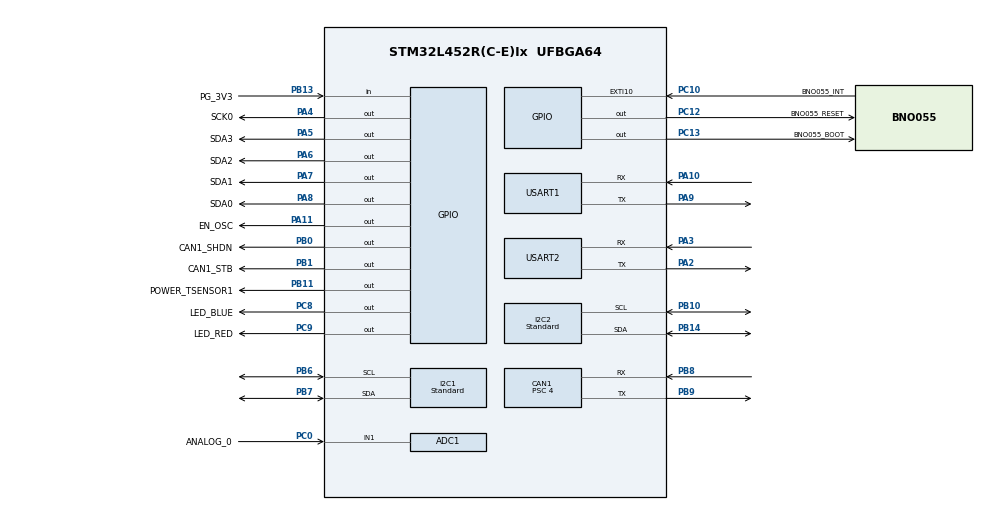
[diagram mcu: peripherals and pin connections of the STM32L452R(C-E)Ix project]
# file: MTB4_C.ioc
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ADC1.Channel-1\#ChannelRegularConversion=ADC_CHANNEL_1
ADC1.NbrOfConversionFlag=1
ADC1.OffsetNumber-1\#ChannelRegularConversion=ADC_OFFSET_NONE
ADC1.Rank-1\#ChannelRegularConversion=1
ADC1.SamplingTime-1\#ChannelRegularConversion=ADC_SAMPLETIME_2CYCLES_5
ADC1.master=1
CAN1.ABOM=ENABLE
CAN1.AWUM=ENABLE
CAN1.BS1=CAN_BS1_4TQ
CAN1.BS2=CAN_BS2_3TQ
CAN1.CalculateBaudRate=1000000
CAN1.CalculateTimeBit=1000
CAN1.CalculateTimeQuantum=125.0
CAN1.NART=ENABLE
CAN1.Prescaler=4
Dma.I2C1_RX.3.Direction=DMA_PERIPH_TO_MEMORY
Dma.I2C1_RX.3.Instance=DMA1_Channel7
Dma.I2C1_RX.3.MemDataAlignment=DMA_MDATAALIGN_BYTE
Dma.I2C1_RX.3.MemInc=DMA_MINC_ENABLE
Dma.I2C1_RX.3.Mode=DMA_NORMAL
Dma.I2C1_RX.3.PeriphDataAlignment=DMA_PDATAALIGN_BYTE
Dma.I2C1_RX.3.PeriphInc=DMA_PINC_DISABLE
Dma.I2C1_RX.3.Priority=DMA_PRIORITY_LOW
Dma.I2C1_TX.2.Direction=DMA_MEMORY_TO_PERIPH
Dma.I2C1_TX.2.Instance=DMA1_Channel6
Dma.I2C1_TX.2.MemDataAlignment=DMA_MDATAALIGN_BYTE
Dma.I2C1_TX.2.MemInc=DMA_MINC_ENABLE
Dma.I2C1_TX.2.Mode=DMA_NORMAL
Dma.I2C1_TX.2.PeriphDataAlignment=DMA_PDATAALIGN_BYTE
Dma.I2C1_TX.2.PeriphInc=DMA_PINC_DISABLE
Dma.I2C1_TX.2.Priority=DMA_PRIORITY_LOW
Dma.I2C2_RX.1.Direction=DMA_PERIPH_TO_MEMORY
Dma.I2C2_RX.1.Instance=DMA1_Channel5
Dma.I2C2_RX.1.MemDataAlignment=DMA_MDATAALIGN_BYTE
Dma.I2C2_RX.1.MemInc=DMA_MINC_ENABLE
Dma.I2C2_RX.1.Mode=DMA_NORMAL
Dma.I2C2_RX.1.PeriphDataAlignment=DMA_PDATAALIGN_BYTE
Dma.I2C2_RX.1.PeriphInc=DMA_PINC_DISABLE
Dma.I2C2_RX.1.Priority=DMA_PRIORITY_LOW
Dma.I2C2_TX.0.Direction=DMA_MEMORY_TO_PERIPH
Dma.I2C2_TX.0.Instance=DMA1_Channel4
Dma.I2C2_TX.0.MemDataAlignment=DMA_MDATAALIGN_BYTE
Dma.I2C2_TX.0.MemInc=DMA_MINC_ENABLE
Dma.I2C2_TX.0.Mode=DMA_NORMAL
Dma.I2C2_TX.0.PeriphDataAlignment=DMA_PDATAALIGN_BYTE
Dma.I2C2_TX.0.PeriphInc=DMA_PINC_DISABLE
Dma.I2C2_TX.0.Priority=DMA_PRIORITY_LOW
Dma.Request0=I2C2_TX
Dma.Request1=I2C2_RX
Dma.Request2=I2C1_TX
Dma.Request3=I2C1_RX
Dma.Request4=USART1_TX
Dma.Request5=USART1_RX
Dma.USART1_RX.5.Direction=DMA_PERIPH_TO_MEMORY
Dma.USART1_RX.5.Instance=DMA2_Channel7
Dma.USART1_RX.5.MemDataAlignment=DMA_MDATAALIGN_BYTE
Dma.USART1_RX.5.MemInc=DMA_MINC_ENABLE
Dma.USART1_RX.5.Mode=DMA_NORMAL
Dma.USART1_RX.5.PeriphDataAlignment=DMA_PDATAALIGN_BYTE
Dma.USART1_RX.5.PeriphInc=DMA_PINC_DISABLE
Dma.USART1_RX.5.Priority=DMA_PRIORITY_LOW
Dma.USART1_TX.4.Direction=DMA_MEMORY_TO_PERIPH
Dma.USART1_TX.4.Instance=DMA2_Channel6
Dma.USART1_TX.4.MemDataAlignment=DMA_MDATAALIGN_BYTE
Dma.USART1_TX.4.MemInc=DMA_MINC_ENABLE
Dma.USART1_TX.4.Mode=DMA_NORMAL
Dma.USART1_TX.4.PeriphDataAlignment=DMA_PDATAALIGN_BYTE
Dma.USART1_TX.4.PeriphInc=DMA_PINC_DISABLE
Dma.USART1_TX.4.Priority=DMA_PRIORITY_LOW
I2C1.CustomTiming=Disabled
I2C1.I2C_Speed_Mode=I2C_Standard
I2C1.NoStretchMode=I2C_NOSTRETCH_DISABLE
I2C1.Timing=0x00707CBB
I2C2.I2C_Speed_Mode=I2C_Standard
I2C2.NoStretchMode=I2C_NOSTRETCH_DISABLE
I2C2.Timing=0x00707CBB
Mcu.Family=STM32L4
Mcu.Name=STM32L452R(C-E)Ix
Mcu.Package=UFBGA64
NVIC.CAN1_RX0_IRQn=true\:0\:0\:false\:false\:true\:true\:true\:true
NVIC.CAN1_TX_IRQn=true\:0\:0\:false\:false\:true\:true\:true\:true
NVIC.DMA1_Channel4_IRQn=true\:0\:0\:false\:false\:true\:false\:true\:true
NVIC.DMA1_Channel5_IRQn=true\:0\:0\:false\:false\:true\:false\:true\:true
NVIC.DMA1_Channel6_IRQn=true\:0\:0\:false\:false\:true\:false\:true\:true
NVIC.DMA1_Channel7_IRQn=true\:0\:0\:false\:false\:true\:false\:true\:true
NVIC.DMA2_Channel6_IRQn=true\:0\:0\:false\:false\:true\:false\:true\:true
NVIC.DMA2_Channel7_IRQn=true\:0\:0\:false\:false\:true\:false\:true\:true
NVIC.I2C1_ER_IRQn=true\:0\:0\:false\:false\:true\:true\:true\:true
NVIC.I2C1_EV_IRQn=true\:0\:0\:false\:false\:true\:true\:true\:true
NVIC.I2C2_ER_IRQn=true\:0\:0\:false\:false\:true\:true\:true\:true
NVIC.I2C2_EV_IRQn=true\:0\:0\:false\:false\:true\:true\:true\:true
NVIC.PriorityGroup=NVIC_PRIORITYGROUP_4
NVIC.TIM6_DAC_IRQn=true\:0\:0\:false\:false\:true\:true\:true\:true
PA10.Mode=Asynchronous
PA10.Signal=USART1_RX
PA11.GPIO_Label=EN_OSC
PA11.Signal=GPIO_Output
PA13\ (JTMS/SWDIO).Mode=Serial_Wire
PA13\ (JTMS/SWDIO).Signal=SYS_JTMS-SWDIO
PA14\ (JTCK/SWCLK).Mode=Serial_Wire
PA14\ (JTCK/SWCLK).Signal=SYS_JTCK-SWCLK
PA2.Mode=Asynchronous
PA2.Signal=USART2_TX
PA3.Mode=Asynchronous
PA3.Signal=USART2_RX
PA4.GPIO_Label=SCK0
PA4.Signal=GPIO_Output
PA5.GPIO_Label=SDA3
PA5.Signal=GPIO_Output
PA6.GPIO_Label=SDA2
PA6.Signal=GPIO_Output
PA7.GPIO_Label=SDA1
PA7.Signal=GPIO_Output
PA8.GPIO_Label=SDA0
PA8.Signal=GPIO_Output
PA9.Mode=Asynchronous
PA9.Signal=USART1_TX
PB0.GPIO_Label=CAN1_SHDN
PB0.Signal=GPIO_Output
PB1.GPIO_Label=CAN1_STB
PB1.Signal=GPIO_Output
PB10.GPIO_Pu=GPIO_PULLUP
PB10.Mode=I2C
PB10.Signal=I2C2_SCL
PB11.GPIO_Label=POWER_TSENSOR1
PB11.Signal=GPIO_Output
PB13.GPIO_Label=PG_3V3
PB13.Signal=GPIO_Input
PB14.GPIO_Pu=GPIO_PULLUP
PB14.Mode=I2C
PB14.Signal=I2C2_SDA
PB6.GPIO_Pu=GPIO_PULLUP
PB6.Mode=I2C
PB6.Signal=I2C1_SCL
PB7.GPIO_Pu=GPIO_PULLUP
PB7.Mode=I2C
PB7.Signal=I2C1_SDA
PB8.Mode=CAN_Activate
PB8.Signal=CAN1_RX
PB9.Mode=CAN_Activate
PB9.Signal=CAN1_TX
PC0.GPIO_Label=ANALOG_0
PC0.Signal=ADCx_IN1
PC10.GPIO_Label=BNO055_INT
PC10.Signal=GPXTI10
PC12.GPIO_Label=BNO055_RESET
PC12.Signal=GPIO_Output
PC13.GPIO_Label=BNO055_BOOT
PC13.Signal=GPIO_Output
PC8.GPIO_Label=LED_BLUE
PC8.Signal=GPIO_Output
PC9.GPIO_Label=LED_RED
PC9.Signal=GPIO_Output
PH0-OSC_IN\ (PH0).Mode=HSE-External-Clock-Source
PH0-OSC_IN\ (PH0).Signal=RCC_OSC_IN
ProjectManager.HeapSize=0x200
ProjectManager.StackSize=0x400
ProjectManager.TargetToolchain=MDK-ARM V5.32
RCC.ADCFreq_Value=32000000
RCC.AHBFreq_Value=32000000
RCC.APB1Freq_Value=32000000
RCC.APB1TimFreq_Value=32000000
RCC.APB2Freq_Value=32000000
RCC.APB2TimFreq_Value=32000000
RCC.CortexFreq_Value=32000000
RCC.HCLKFreq_Value=32000000
RCC.HSE_VALUE=10000000
RCC.HSI48_VALUE=48000000
RCC.HSI_VALUE=16000000
RCC.LSE_VALUE=32768
RCC.MSI_VALUE=4000000
RCC.PLLM=4
RCC.PLLN=16
RCC.PLLSAI1N=16
RCC.PLLSAI1Q=RCC_PLLQ_DIV4
RCC.PLLSourceVirtual=RCC_PLLSOURCE_HSI
RCC.SYSCLKFreq_VALUE=32000000
RCC.SYSCLKSource=RCC_SYSCLKSOURCE_PLLCLK
RCC.USBFreq_Value=16000000
RCC.VCOOutputFreq_Value=64000000
SH.ADCx_IN1.0=ADC1_IN1,IN1-Single-Ended
TIM6.Period=1
TIM6.Prescaler=1000
USART1.VirtualMode-Asynchronous=VM_ASYNC
USART2.VirtualMode-Asynchronous=VM_ASYNC
VP_RNG_VS_RNG.Mode=RNG_Activate
VP_TIM6_VS_ClockSourceINT.Mode=Enable_Timer
board=custom

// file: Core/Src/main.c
/* USER CODE BEGIN Header */
/**
  ******************************************************************************
  * @file           : main.c
  * @brief          : Main program body
  ******************************************************************************
  * @attention
  *
  * Copyright (c) 2022 STMicroelectronics.
  * All rights reserved.
  *
  * This software is licensed under terms that can be found in the LICENSE file
  * in the root directory of this software component.
  * If no LICENSE file comes with this software, it is provided AS-IS.
  *
  ******************************************************************************
  */
/* USER CODE END Header */
#include "main.h"
#include "adc.h"
#include "can.h"
#include "dma.h"
#include "i2c.h"
#include "tim.h"
#include "usart.h"
#include "gpio.h"

void SystemClock_Config(void);

int main(void)
{

  /* MCU Configuration--------------------------------------------------------*/

  /* Reset of all peripherals, Initializes the Flash interface and the Systick. */
  HAL_Init();

  /* Configure the system clock */
  SystemClock_Config();

  /* Initialize all configured peripherals */
  MX_GPIO_Init();
  MX_CAN1_Init();
  MX_I2C1_Init();
  MX_I2C2_Init();
  MX_USART1_UART_Init();
  MX_DMA_Init();
  MX_TIM6_Init();
  MX_USART2_UART_Init();
  MX_ADC1_Init();

  /* Infinite loop */
  /* USER CODE BEGIN WHILE */
  HAL_GPIO_WritePin(LED_RED_GPIO_Port, LED_RED_Pin, GPIO_PIN_SET);
  HAL_GPIO_WritePin(LED_BLUE_GPIO_Port, LED_BLUE_Pin, GPIO_PIN_SET);

	while (1)
  {
    /* USER CODE END WHILE */

  }
}

void SystemClock_Config(void)
{
  RCC_OscInitTypeDef RCC_OscInitStruct = {0};
  RCC_ClkInitTypeDef RCC_ClkInitStruct = {0};

  /** Configure the main internal regulator output voltage
  */
  if (HAL_PWREx_ControlVoltageScaling(PWR_REGULATOR_VOLTAGE_SCALE1) != HAL_OK)
  {
    Error_Handler();
  }

  /** Initializes the RCC Oscillators according to the specified parameters
  * in the RCC_OscInitTypeDef structure.
  */
  RCC_OscInitStruct.OscillatorType = RCC_OSCILLATORTYPE_HSI;
  RCC_OscInitStruct.HSIState = RCC_HSI_ON;
  RCC_OscInitStruct.HSICalibrationValue = RCC_HSICALIBRATION_DEFAULT;
  RCC_OscInitStruct.PLL.PLLState = RCC_PLL_NONE;
  if (HAL_RCC_OscConfig(&RCC_OscInitStruct) != HAL_OK)
  {
    Error_Handler();
  }

  /** Initializes the CPU, AHB and APB buses clocks
  */
  RCC_ClkInitStruct.ClockType = RCC_CLOCKTYPE_HCLK|RCC_CLOCKTYPE_SYSCLK
                              |RCC_CLOCKTYPE_PCLK1|RCC_CLOCKTYPE_PCLK2;
  RCC_ClkInitStruct.SYSCLKSource = RCC_SYSCLKSOURCE_HSI;
  RCC_ClkInitStruct.AHBCLKDivider = RCC_SYSCLK_DIV1;
  RCC_ClkInitStruct.APB1CLKDivider = RCC_HCLK_DIV1;
  RCC_ClkInitStruct.APB2CLKDivider = RCC_HCLK_DIV1;

  if (HAL_RCC_ClockConfig(&RCC_ClkInitStruct, FLASH_LATENCY_0) != HAL_OK)
  {
    Error_Handler();
  }
}

void Error_Handler(void)
{
  __disable_irq();
  while (1)
  {
  }
}
